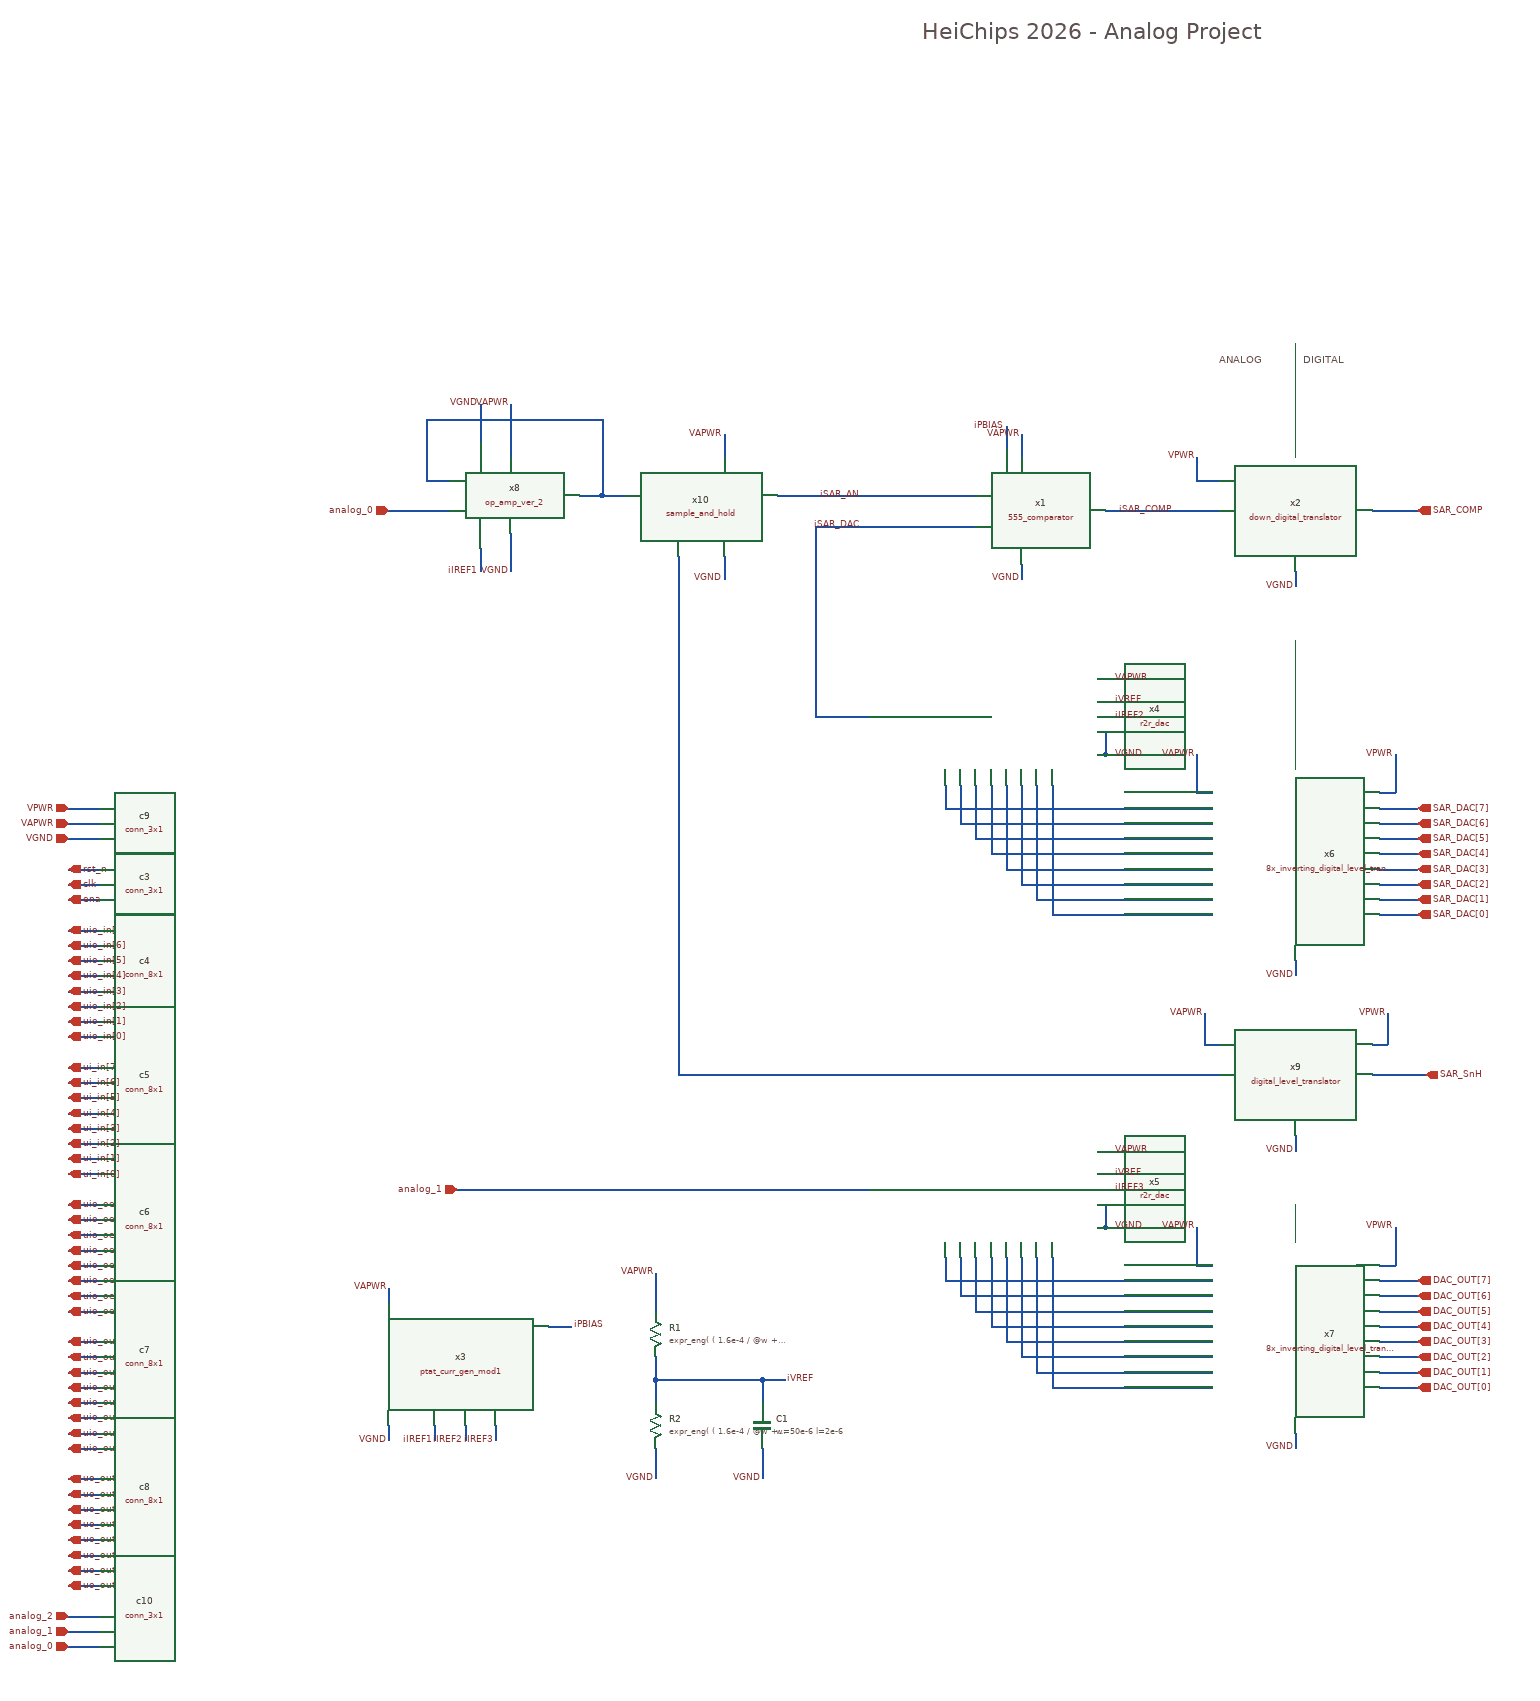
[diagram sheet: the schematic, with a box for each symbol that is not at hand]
v {xschem version=3.4.8RC file_version=1.3}
G {}
K {}
V {}
S {}
F {}
E {}
L 4 1770 -1970 1770 -1820 {fill = false
dash = 16}
L 4 1770 -1580 1770 -1410 {fill = false
dash = 16}
L 4 1770 -840 1770 -790 {fill = false
dash = 16}
T {HeiChips 2026 - Analog Project} 1280 -2390 0 0 1 1 {}
T {ANALOG} 1670 -1960 0 0 0.4 0.4 {}
T {DIGITAL} 1780 -1960 0 0 0.4 0.4 {}
N 580 -730 580 -710 {lab=VAPWR}
N 1410 -1850 1410 -1820 {lab=VAPWR}
N 580 -550 580 -530 {lab=VGND}
N 1410 -1680 1410 -1660 {lab=VGND}
N 1770 -1670 1770 -1650 {lab=VGND}
N 1640 -1790 1670 -1790 {lab=VPWR}
N 1640 -1820 1640 -1790 {lab=VPWR}
N 1900 -1430 1900 -1380 {lab=VPWR}
N 1880 -1380 1900 -1380 {lab=VPWR}
N 1900 -810 1900 -760 {lab=VPWR}
N 1880 -760 1900 -760 {lab=VPWR}
N 1640 -1380 1660 -1380 {lab=VAPWR}
N 1640 -1430 1640 -1380 {lab=VAPWR}
N 1640 -760 1660 -760 {lab=VAPWR}
N 1640 -810 1640 -760 {lab=VAPWR}
N 1770 -540 1770 -520 {lab=VGND}
N 1770 -1160 1770 -1140 {lab=VGND}
N 1310 -1360 1660 -1360 {lab=#net1}
N 1310 -1390 1310 -1360 {lab=#net1}
N 1330 -1340 1660 -1340 {lab=#net2}
N 1330 -1390 1330 -1340 {lab=#net2}
N 1350 -1320 1660 -1320 {lab=#net3}
N 1350 -1390 1350 -1320 {lab=#net3}
N 1370 -1300 1660 -1300 {lab=#net4}
N 1370 -1390 1370 -1300 {lab=#net4}
N 1390 -1280 1660 -1280 {lab=#net5}
N 1390 -1390 1390 -1280 {lab=#net5}
N 1410 -1260 1660 -1260 {lab=#net6}
N 1410 -1390 1410 -1260 {lab=#net6}
N 1430 -1240 1660 -1240 {lab=#net7}
N 1430 -1390 1430 -1240 {lab=#net7}
N 1450 -1220 1660 -1220 {lab=#net8}
N 1450 -1390 1450 -1220 {lab=#net8}
N 1310 -740 1660 -740 {lab=#net9}
N 1310 -770 1310 -740 {lab=#net9}
N 1330 -720 1660 -720 {lab=#net10}
N 1330 -770 1330 -720 {lab=#net10}
N 1350 -700 1660 -700 {lab=#net11}
N 1350 -770 1350 -700 {lab=#net11}
N 1370 -680 1660 -680 {lab=#net12}
N 1370 -770 1370 -680 {lab=#net12}
N 1390 -660 1660 -660 {lab=#net13}
N 1390 -770 1390 -660 {lab=#net13}
N 1430 -620 1660 -620 {lab=#net14}
N 1430 -770 1430 -620 {lab=#net14}
N 1410 -640 1660 -640 {lab=#net15}
N 1410 -770 1410 -640 {lab=#net15}
N 1450 -600 1660 -600 {lab=#net16}
N 1450 -770 1450 -600 {lab=#net16}
N 1520 -1430 1530 -1430 {lab=VGND}
N 1520 -810 1530 -810 {lab=VGND}
N 1510 -910 1530 -910 {lab=VAPWR}
N 1510 -1530 1530 -1530 {lab=VAPWR}
N 1510 -1460 1520 -1460 {lab=VGND}
N 1520 -1460 1520 -1430 {lab=VGND}
N 1510 -1430 1520 -1430 {lab=VGND}
N 1510 -840 1520 -840 {lab=VGND}
N 1520 -840 1520 -810 {lab=VGND}
N 1510 -810 1520 -810 {lab=VGND}
N 1520 -1750 1670 -1750 {lab=iSAR_COMP}
N 1140 -1730 1350 -1730 {lab=iSAR_DAC}
N 1140 -1730 1140 -1480 {lab=iSAR_DAC}
N 1140 -1480 1210 -1480 {lab=iSAR_DAC}
N 630 -1790 660 -1790 {lab=#net17}
N 630 -1870 630 -1790 {lab=#net17}
N 630 -1870 860 -1870 {lab=#net17}
N 830 -1770 860 -1770 {lab=#net17}
N 860 -1870 860 -1770 {lab=#net17}
N 740 -1720 740 -1670 {lab=VGND}
N 740 -1890 740 -1820 {lab=VAPWR}
N 700 -1890 700 -1840 {lab=VGND}
N 720 -550 720 -530 {lab=iIREF3}
N 680 -550 680 -530 {lab=iIREF2}
N 640 -550 640 -530 {lab=iIREF1}
N 1510 -860 1530 -860 {lab=iIREF3}
N 1510 -1480 1530 -1480 {lab=iIREF2}
N 700 -1700 700 -1670 {lab=iIREF1}
N 930 -640 930 -610 {lab=iVREF}
N 930 -610 1070 -610 {lab=iVREF}
N 1070 -610 1070 -580 {lab=iVREF}
N 930 -610 930 -580 {lab=iVREF}
N 1070 -610 1100 -610 {lab=iVREF}
N 930 -750 930 -700 {lab=VAPWR}
N 930 -520 930 -480 {lab=VGND}
N 1510 -1500 1530 -1500 {lab=iVREF}
N 1510 -880 1530 -880 {lab=iVREF}
N 580 -1750 660 -1750 {lab=analog_0}
N 670 -860 1210 -860 {lab=analog_1}
N 790 -680 820 -680 {lab=iPBIAS}
N 1390 -1860 1390 -1830 {lab=iPBIAS}
N 1650 -1050 1670 -1050 {lab=VAPWR}
N 1650 -1090 1650 -1050 {lab=VAPWR}
N 1870 -1050 1890 -1050 {lab=VPWR}
N 1890 -1090 1890 -1050 {lab=VPWR}
N 1770 -930 1770 -910 {lab=VGND}
N 960 -1010 1670 -1010 {lab=#net18}
N 1880 -600 1930 -600 {lab=DAC_OUT[0]}
N 1880 -620 1930 -620 {lab=DAC_OUT[1]}
N 1880 -640 1930 -640 {lab=DAC_OUT[2]}
N 1880 -660 1930 -660 {lab=DAC_OUT[3]}
N 1880 -700 1930 -700 {lab=DAC_OUT[5]}
N 1880 -680 1930 -680 {lab=DAC_OUT[4]}
N 1880 -720 1930 -720 {lab=DAC_OUT[6]}
N 1880 -740 1930 -740 {lab=DAC_OUT[7]}
N 1880 -1220 1930 -1220 {lab=SAR_DAC[0]}
N 1880 -1240 1930 -1240 {lab=SAR_DAC[1]}
N 1880 -1260 1930 -1260 {lab=SAR_DAC[2]}
N 1880 -1280 1930 -1280 {lab=SAR_DAC[3]}
N 1880 -1300 1930 -1300 {lab=SAR_DAC[4]}
N 1880 -1320 1930 -1320 {lab=SAR_DAC[5]}
N 1880 -1340 1930 -1340 {lab=SAR_DAC[6]}
N 1880 -1360 1930 -1360 {lab=SAR_DAC[7]}
N 1870 -1750 1930 -1750 {lab=SAR_COMP}
N 1870 -1010 1940 -1010 {lab=SAR_SnH}
N 1070 -520 1070 -480 {lab=VGND}
N 160 -1260 200 -1260 {lab=clk}
N 160 -1240 200 -1240 {lab=ena}
N 160 -1280 200 -1280 {lab=rst_n}
N 160 -1200 200 -1200 {lab=uio_in[7]}
N 160 -1180 200 -1180 {lab=uio_in[6]}
N 160 -1160 200 -1160 {lab=uio_in[5]}
N 160 -1140 200 -1140 {lab=uio_in[4]}
N 160 -1120 200 -1120 {lab=uio_in[3]}
N 160 -1100 200 -1100 {lab=uio_in[2]}
N 160 -1080 200 -1080 {lab=uio_in[1]}
N 160 -1060 200 -1060 {lab=uio_in[0]}
N 160 -1020 200 -1020 {lab=ui_in[7]}
N 160 -1000 200 -1000 {lab=ui_in[6]}
N 160 -980 200 -980 {lab=ui_in[5]}
N 160 -960 200 -960 {lab=ui_in[4]}
N 160 -940 200 -940 {lab=ui_in[3]}
N 160 -920 200 -920 {lab=ui_in[2]}
N 160 -900 200 -900 {lab=ui_in[1]}
N 160 -880 200 -880 {lab=ui_in[0]}
N 160 -840 200 -840 {lab=uio_oe[7]}
N 160 -820 200 -820 {lab=uio_oe[6]}
N 160 -800 200 -800 {lab=uio_oe[5]}
N 160 -780 200 -780 {lab=uio_oe[4]}
N 160 -760 200 -760 {lab=uio_oe[3]}
N 160 -740 200 -740 {lab=uio_oe[2]}
N 160 -720 200 -720 {lab=uio_oe[1]}
N 160 -700 200 -700 {lab=uio_oe[0]}
N 160 -660 200 -660 {lab=uio_out[7]}
N 160 -640 200 -640 {lab=uio_out[6]}
N 160 -620 200 -620 {lab=uio_out[5]}
N 160 -600 200 -600 {lab=uio_out[4]}
N 160 -580 200 -580 {lab=uio_out[3]}
N 160 -560 200 -560 {lab=uio_out[2]}
N 160 -540 200 -540 {lab=uio_out[1]}
N 160 -520 200 -520 {lab=uio_out[0]}
N 160 -480 200 -480 {lab=uo_out[7]}
N 160 -460 200 -460 {lab=uo_out[6]}
N 160 -440 200 -440 {lab=uo_out[5]}
N 160 -420 200 -420 {lab=uo_out[4]}
N 160 -400 200 -400 {lab=uo_out[3]}
N 160 -380 200 -380 {lab=uo_out[2]}
N 160 -360 200 -360 {lab=uo_out[1]}
N 160 -340 200 -340 {lab=uo_out[0]}
N 160 -1340 200 -1340 {lab=VAPWR}
N 160 -1320 200 -1320 {lab=VGND}
N 160 -1360 200 -1360 {lab=VPWR}
N 160 -300 200 -300 {lab=analog_2}
N 160 -280 200 -280 {lab=analog_1}
N 160 -260 200 -260 {lab=analog_0}
N 860 -1770 890 -1770 {lab=#net17}
N 1090 -1770 1350 -1770 {lab=iSAR_AN}
N 960 -1690 960 -1010 {lab=#net18}
N 1020 -1690 1020 -1660 {lab=VGND}
N 1020 -1850 1020 -1820 {lab=VAPWR}
C {title-2.sym} 0 0 0 0 {name=l1 author="ABCDEFG" rev=1.0 lock=true}
C {555_comparator.sym} 1370 -1750 0 0 {name=x1}
C {down_digital_translator.sym} 1690 -1690 0 0 {name=x2}
C {ptat_curr_gen_mod1.sym} 550 -570 0 0 {name=x3}
C {r2r_dac.sym} 1570 -1320 0 1 {name=x4}
C {r2r_dac.sym} 1570 -700 0 1 {name=x5}
C {8x_inverting_digital_level_translator.sym} 1860 -1180 0 1 {name=x6}
C {8x_inverting_digital_level_translator.sym} 1860 -560 0 1 {name=x7}
C {lab_pin.sym} 580 -730 1 0 {name=p1 sig_type=std_logic lab=VAPWR
}
C {lab_pin.sym} 1410 -1850 1 0 {name=p2 sig_type=std_logic lab=VAPWR
}
C {lab_pin.sym} 580 -530 3 0 {name=p5 sig_type=std_logic lab=VGND
}
C {lab_pin.sym} 1410 -1660 3 0 {name=p6 sig_type=std_logic lab=VGND
}
C {lab_pin.sym} 1770 -1650 3 0 {name=p7 sig_type=std_logic lab=VGND
}
C {lab_pin.sym} 1640 -1820 1 0 {name=p10 sig_type=std_logic lab=VPWR
}
C {lab_pin.sym} 1900 -1430 1 0 {name=p11 sig_type=std_logic lab=VPWR
}
C {lab_pin.sym} 1900 -810 1 0 {name=p19 sig_type=std_logic lab=VPWR
}
C {lab_pin.sym} 1640 -1430 1 0 {name=p20 sig_type=std_logic lab=VAPWR
}
C {lab_pin.sym} 1640 -810 1 0 {name=p21 sig_type=std_logic lab=VAPWR
}
C {lab_pin.sym} 1770 -1140 3 0 {name=p22 sig_type=std_logic lab=VGND
}
C {lab_pin.sym} 1770 -520 3 0 {name=p23 sig_type=std_logic lab=VGND
}
C {lab_pin.sym} 1530 -1530 2 0 {name=p24 sig_type=std_logic lab=VAPWR
}
C {lab_pin.sym} 1530 -910 2 0 {name=p67 sig_type=std_logic lab=VAPWR
}
C {lab_pin.sym} 1530 -810 2 0 {name=p68 sig_type=std_logic lab=VGND
}
C {lab_pin.sym} 1530 -1430 2 0 {name=p69 sig_type=std_logic lab=VGND
}
C {lab_pin.sym} 820 -680 2 0 {name=p70 sig_type=std_logic lab=iPBIAS
}
C {op_amp_ver_2.sym} 730 -1770 0 0 {name=x8}
C {lab_pin.sym} 740 -1890 1 0 {name=p71 sig_type=std_logic lab=VAPWR
}
C {lab_pin.sym} 740 -1670 3 0 {name=p72 sig_type=std_logic lab=VGND
}
C {lab_pin.sym} 700 -1890 1 0 {name=p73 sig_type=std_logic lab=VGND
}
C {lab_pin.sym} 640 -530 3 0 {name=p74 sig_type=std_logic lab=iIREF1
}
C {lab_pin.sym} 680 -530 3 0 {name=p75 sig_type=std_logic lab=iIREF2

}
C {lab_pin.sym} 720 -530 3 0 {name=p76 sig_type=std_logic lab=iIREF3
}
C {lab_pin.sym} 700 -1670 3 0 {name=p77 sig_type=std_logic lab=iIREF1
}
C {lab_pin.sym} 1530 -1480 2 0 {name=p78 sig_type=std_logic lab=iIREF2

}
C {lab_pin.sym} 1530 -860 2 0 {name=p79 sig_type=std_logic lab=iIREF3
}
C {sg13cmos5l_pr/rhigh.sym} 930 -670 0 0 {name=R1
w=0.5e-6
l=50e-6
model=rhigh
body=VGND
spiceprefix=X
b=0
 m=1
  mm_ok=1
value="expr_eng(  ( 1.6e-4 / @w + 1360.0 * ( (@b + 1)* @l + ( 1.081*( @w - 0.04e-6 ) + 0.18e-6 )*@b ) / ( @w - 0.04e-6 ) ) / @m  )"
}
C {sg13cmos5l_pr/rhigh.sym} 930 -550 0 0 {name=R2
w=0.5e-6
l=50e-6
model=rhigh
body=VGND
spiceprefix=X
b=0
 m=1
  mm_ok=1
value="expr_eng(  ( 1.6e-4 / @w + 1360.0 * ( (@b + 1)* @l + ( 1.081*( @w - 0.04e-6 ) + 0.18e-6 )*@b ) / ( @w - 0.04e-6 ) ) / @m  )"
}
C {sg13cmos5l_pr/cap_cmomi.sym} 1070 -550 0 0 {name=C1
model=cap_cmomi
w=50e-6
l=2e-6
mmin=2
mmax=3
feed=double
subblock=0
m=1
mm_ok=1
spiceprefix=X
}
C {lab_pin.sym} 930 -750 1 0 {name=p80 sig_type=std_logic lab=VAPWR
}
C {lab_pin.sym} 930 -480 3 0 {name=p81 sig_type=std_logic lab=VGND
}
C {lab_pin.sym} 1100 -610 2 0 {name=p82 sig_type=std_logic lab=iVREF
}
C {lab_pin.sym} 1530 -880 2 0 {name=p83 sig_type=std_logic lab=iVREF
}
C {lab_pin.sym} 1530 -1500 2 0 {name=p84 sig_type=std_logic lab=iVREF
}
C {devices/iopin.sym} 580 -1750 2 0 {name=p85 lab=analog_0}
C {devices/iopin.sym} 670 -860 2 0 {name=p86 lab=analog_1}
C {lab_pin.sym} 1390 -1860 1 0 {name=p87 sig_type=std_logic lab=iPBIAS
}
C {digital_level_translator.sym} 1850 -950 0 1 {name=x9}
C {lab_pin.sym} 1650 -1090 1 0 {name=p88 sig_type=std_logic lab=VAPWR
}
C {lab_pin.sym} 1890 -1090 1 0 {name=p89 sig_type=std_logic lab=VPWR
}
C {lab_pin.sym} 1770 -910 3 0 {name=p90 sig_type=std_logic lab=VGND
}
C {lab_wire.sym} 1200 -1730 0 0 {name=p91 sig_type=std_logic lab=iSAR_DAC}
C {lab_wire.sym} 1610 -1750 0 0 {name=p92 sig_type=std_logic lab=iSAR_COMP}
C {lab_wire.sym} 1200 -1770 0 0 {name=p93 sig_type=std_logic lab=iSAR_AN}
C {devices/ipin.sym} 1930 -600 0 1 {name=p94 lab=DAC_OUT[0]
}
C {devices/ipin.sym} 1930 -620 0 1 {name=p95 lab=DAC_OUT[1]
}
C {devices/ipin.sym} 1930 -640 0 1 {name=p96 lab=DAC_OUT[2]
}
C {devices/ipin.sym} 1930 -660 0 1 {name=p97 lab=DAC_OUT[3]
}
C {devices/ipin.sym} 1930 -680 0 1 {name=p98 lab=DAC_OUT[4]
}
C {devices/ipin.sym} 1930 -700 0 1 {name=p99 lab=DAC_OUT[5]
}
C {devices/ipin.sym} 1930 -720 0 1 {name=p100 lab=DAC_OUT[6]
}
C {devices/ipin.sym} 1930 -740 0 1 {name=p101 lab=DAC_OUT[7]
}
C {devices/ipin.sym} 1930 -1220 0 1 {name=p102 lab=SAR_DAC[0]
}
C {devices/ipin.sym} 1930 -1240 0 1 {name=p103 lab=SAR_DAC[1]
}
C {devices/ipin.sym} 1930 -1260 0 1 {name=p104 lab=SAR_DAC[2]
}
C {devices/ipin.sym} 1930 -1280 0 1 {name=p105 lab=SAR_DAC[3]
}
C {devices/ipin.sym} 1930 -1300 0 1 {name=p106 lab=SAR_DAC[4]
}
C {devices/ipin.sym} 1930 -1320 0 1 {name=p107 lab=SAR_DAC[5]
}
C {devices/ipin.sym} 1930 -1340 0 1 {name=p108 lab=SAR_DAC[6]
}
C {devices/ipin.sym} 1930 -1360 0 1 {name=p109 lab=SAR_DAC[7]
}
C {devices/opin.sym} 1930 -1750 0 0 {name=p110 lab=SAR_COMP}
C {devices/ipin.sym} 1940 -1010 0 1 {name=p111 lab=SAR_SnH
}
C {lab_pin.sym} 1070 -480 3 0 {name=p8 sig_type=std_logic lab=VGND
}
C {devices/ipin.sym} 160 -1280 2 1 {name=p30 lab=rst_n}
C {devices/ipin.sym} 160 -1260 2 1 {name=p31 lab=clk}
C {devices/ipin.sym} 160 -1240 2 1 {name=p32 lab=ena}
C {devices/ipin.sym} 160 -1200 2 1 {name=p33 lab=uio_in[7]}
C {conn_3x1.sym} 220 -1260 0 1 {name=c3 footprint=connector(3,1)}
C {conn_8x1.sym} 220 -1180 0 1 {name=c4 footprint=connector(8,1)}
C {devices/ipin.sym} 160 -1020 2 1 {name=p3 lab=ui_in[7]}
C {conn_8x1.sym} 220 -1000 0 1 {name=c5 footprint=connector(8,1)}
C {devices/opin.sym} 160 -840 2 0 {name=p18 lab=uio_oe[7]}
C {devices/opin.sym} 160 -820 2 0 {name=p27 lab=uio_oe[6]}
C {devices/opin.sym} 160 -800 2 0 {name=p28 lab=uio_oe[5]}
C {devices/opin.sym} 160 -780 2 0 {name=p29 lab=uio_oe[4]}
C {devices/opin.sym} 160 -760 2 0 {name=p41 lab=uio_oe[3]}
C {devices/opin.sym} 160 -740 2 0 {name=p42 lab=uio_oe[2]}
C {devices/opin.sym} 160 -720 2 0 {name=p43 lab=uio_oe[1]}
C {devices/opin.sym} 160 -700 2 0 {name=p44 lab=uio_oe[0]}
C {conn_8x1.sym} 220 -820 0 1 {name=c6 footprint=connector(8,1)}
C {devices/opin.sym} 160 -660 2 0 {name=p45 lab=uio_out[7]}
C {devices/opin.sym} 160 -640 2 0 {name=p46 lab=uio_out[6]}
C {devices/opin.sym} 160 -620 2 0 {name=p47 lab=uio_out[5]}
C {devices/opin.sym} 160 -600 2 0 {name=p48 lab=uio_out[4]}
C {devices/opin.sym} 160 -580 2 0 {name=p49 lab=uio_out[3]}
C {devices/opin.sym} 160 -560 2 0 {name=p50 lab=uio_out[2]}
C {devices/opin.sym} 160 -540 2 0 {name=p51 lab=uio_out[1]}
C {devices/opin.sym} 160 -520 2 0 {name=p52 lab=uio_out[0]}
C {conn_8x1.sym} 220 -640 0 1 {name=c7 footprint=connector(8,1)}
C {devices/opin.sym} 160 -480 2 0 {name=p53 lab=uo_out[7]}
C {devices/opin.sym} 160 -460 2 0 {name=p54 lab=uo_out[6]}
C {devices/opin.sym} 160 -440 2 0 {name=p55 lab=uo_out[5]}
C {devices/opin.sym} 160 -420 2 0 {name=p56 lab=uo_out[4]}
C {devices/opin.sym} 160 -400 2 0 {name=p57 lab=uo_out[3]}
C {devices/opin.sym} 160 -380 2 0 {name=p58 lab=uo_out[2]}
C {devices/opin.sym} 160 -360 2 0 {name=p59 lab=uo_out[1]}
C {devices/opin.sym} 160 -340 2 0 {name=p60 lab=uo_out[0]}
C {conn_8x1.sym} 220 -460 0 1 {name=c8 footprint=connector(8,1)}
C {conn_3x1.sym} 220 -1340 0 1 {name=c9 footprint=connector(3,1)}
C {devices/iopin.sym} 160 -1360 2 0 {name=p4 lab=VPWR}
C {devices/iopin.sym} 160 -1320 2 0 {name=p9 lab=VGND}
C {devices/iopin.sym} 160 -1340 2 0 {name=p12 lab=VAPWR}
C {devices/ipin.sym} 160 -1000 2 1 {name=p13 lab=ui_in[6]}
C {devices/ipin.sym} 160 -980 2 1 {name=p14 lab=ui_in[5]}
C {devices/ipin.sym} 160 -960 2 1 {name=p15 lab=ui_in[4]}
C {devices/ipin.sym} 160 -940 2 1 {name=p16 lab=ui_in[3]}
C {devices/ipin.sym} 160 -920 2 1 {name=p17 lab=ui_in[2]}
C {devices/ipin.sym} 160 -900 2 1 {name=p25 lab=ui_in[1]}
C {devices/ipin.sym} 160 -880 2 1 {name=p26 lab=ui_in[0]}
C {devices/ipin.sym} 160 -1180 2 1 {name=p34 lab=uio_in[6]}
C {devices/ipin.sym} 160 -1160 2 1 {name=p35 lab=uio_in[5]}
C {devices/ipin.sym} 160 -1140 2 1 {name=p36 lab=uio_in[4]}
C {devices/ipin.sym} 160 -1120 2 1 {name=p37 lab=uio_in[3]}
C {devices/ipin.sym} 160 -1100 2 1 {name=p38 lab=uio_in[2]}
C {devices/ipin.sym} 160 -1080 2 1 {name=p39 lab=uio_in[1]}
C {devices/ipin.sym} 160 -1060 2 1 {name=p40 lab=uio_in[0]}
C {conn_3x1.sym} 220 -280 0 1 {name=c10 footprint=connector(3,1)}
C {devices/iopin.sym} 160 -300 2 0 {name=p65 lab=analog_2}
C {devices/iopin.sym} 160 -280 2 0 {name=p66 lab=analog_1}
C {devices/iopin.sym} 160 -260 2 0 {name=p115 lab=analog_0}
C {sample_and_hold.sym} 940 -1740 0 0 {name=x10}
C {lab_pin.sym} 1020 -1850 1 0 {name=p61 sig_type=std_logic lab=VAPWR
}
C {lab_pin.sym} 1020 -1660 3 0 {name=p62 sig_type=std_logic lab=VGND
}
